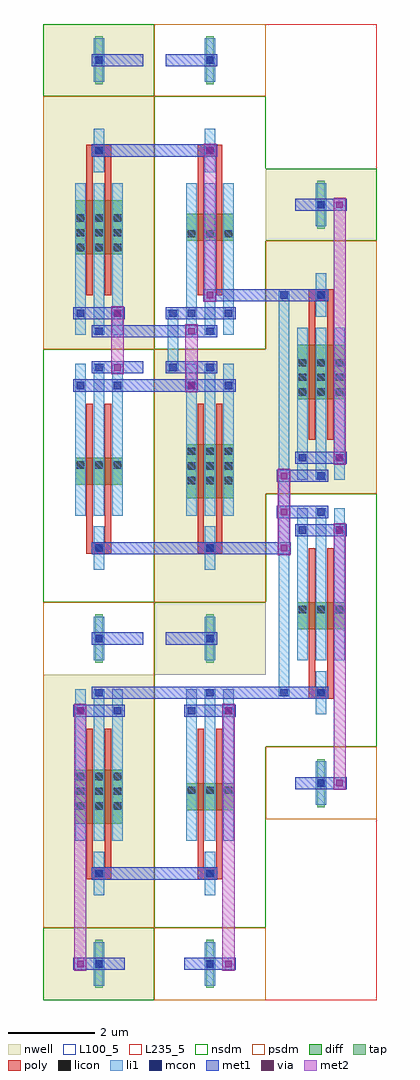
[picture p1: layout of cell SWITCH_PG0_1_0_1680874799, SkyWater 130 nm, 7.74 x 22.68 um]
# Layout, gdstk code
from math import pi, radians
import gdstk
lib = gdstk.Library(unit=1e-6, precision=1e-09)
def R(c, l, rs):  # rectangles x0, y0, x1, y1
    for r in rs: c.add(gdstk.rectangle(r[:2], r[2:], *l))
def A(c, l, x, y, w, h, nx, ny, dx, dy):  # array of equal rectangles
    R(c, l, [(x+i*dx, y+j*dy, x+i*dx+w, y+j*dy+h) for i in range(nx) for j in range(ny)])
def P(c, l, *ps):  # polygons
    for p in ps: c.add(gdstk.Polygon(p, *l))
nwell = (64, 20)
diff = (65, 20)
tap = (65, 44)
poly = (66, 20)
licon = (66, 44)
li1 = (67, 20)
mcon = (67, 44)
met1 = (68, 20)
via = (68, 44)
met2 = (69, 20)
nsdm = (93, 44)
psdm = (94, 20)
L100_5 = (100, 5)
L235_5 = (235, 5)

nmos_s_18927041_x1_y1_16 = lib.new_cell('NMOS_S_18927041_X1_Y1_1680874795_1680874799')
R(nmos_s_18927041_x1_y1_16, diff, [(0.735,2.52,1.845,3.15)])
R(nmos_s_18927041_x1_y1_16, tap, [(1.205,6.16,1.375,7.28)])
R(nmos_s_18927041_x1_y1_16, poly, [(1,1.26,1.15,4.62), (1.43,1.26,1.58,4.62), (1,4.485,1.58,4.755)])
A(nmos_s_18927041_x1_y1_16, licon, 0.775, 2.6, 0.17, 0.17, 3, 1, 0.43, 0)
R(nmos_s_18927041_x1_y1_16, licon, [(1.205,4.535,1.375,4.705), (1.205,6.635,1.375,6.805)])
A(nmos_s_18927041_x1_y1_16, li1, 0.735, 0.335, 0.25, 3.53, 3, 1, 0.43, 0)
R(nmos_s_18927041_x1_y1_16, li1, [(1.165,4.115,1.415,5.125), (1.165,6.215,1.415,7.225)])
R(nmos_s_18927041_x1_y1_16, mcon, [(1.205,0.335,1.375,0.505), (0.775,0.755,0.945,0.925), (1.635,0.755,1.805,0.925), (1.205,4.535,1.375,4.705), (1.205,6.635,1.375,6.805)])
R(nmos_s_18927041_x1_y1_16, met1, [(0.26,0.28,1.46,0.56), (0.69,0.7,1.89,0.98), (0.26,4.48,1.46,4.76), (0.69,6.58,1.89,6.86)])
R(nmos_s_18927041_x1_y1_16, via, [(1.645,0.765,1.795,0.915), (1.645,6.645,1.795,6.795)])
R(nmos_s_18927041_x1_y1_16, met2, [(1.58,0.68,1.86,6.88)])
R(nmos_s_18927041_x1_y1_16, nsdm, [(0,0,2.58,5.88)])
R(nmos_s_18927041_x1_y1_16, psdm, [(0,5.88,2.58,7.56)])
R(nmos_s_18927041_x1_y1_16, L100_5, [(0,0,2.58,7.56)])

pmos_s_92403763_x1_y1_16 = lib.new_cell('PMOS_S_92403763_X1_Y1_1680874798_1680874799')
R(pmos_s_92403763_x1_y1_16, nwell, [(0,0,2.58,7.56)])
R(pmos_s_92403763_x1_y1_16, diff, [(0.735,2.205,1.845,3.465)])
R(pmos_s_92403763_x1_y1_16, tap, [(1.205,6.16,1.375,7.28)])
R(pmos_s_92403763_x1_y1_16, poly, [(1,1.26,1.15,4.62), (1.43,1.26,1.58,4.62), (1,4.485,1.58,4.755)])
A(pmos_s_92403763_x1_y1_16, licon, 0.775, 2.285, 0.17, 0.17, 3, 3, 0.43, 0.34)
R(pmos_s_92403763_x1_y1_16, licon, [(1.205,4.535,1.375,4.705), (1.205,6.635,1.375,6.805)])
A(pmos_s_92403763_x1_y1_16, li1, 0.735, 0.335, 0.25, 3.53, 3, 1, 0.43, 0)
R(pmos_s_92403763_x1_y1_16, li1, [(1.165,4.115,1.415,5.125), (1.165,6.215,1.415,7.225)])
R(pmos_s_92403763_x1_y1_16, mcon, [(1.205,0.335,1.375,0.505), (0.775,0.755,0.945,0.925), (1.635,0.755,1.805,0.925), (1.205,4.535,1.375,4.705), (1.205,6.635,1.375,6.805)])
R(pmos_s_92403763_x1_y1_16, met1, [(0.26,0.28,1.46,0.56), (0.69,0.7,1.89,0.98), (0.26,4.48,1.46,4.76), (0.69,6.58,1.89,6.86)])
R(pmos_s_92403763_x1_y1_16, via, [(1.645,0.765,1.795,0.915), (1.645,6.645,1.795,6.795)])
R(pmos_s_92403763_x1_y1_16, met2, [(1.58,0.68,1.86,6.88)])
R(pmos_s_92403763_x1_y1_16, nsdm, [(0,5.88,2.58,7.56)])
R(pmos_s_92403763_x1_y1_16, psdm, [(0,0,2.58,5.88)])
R(pmos_s_92403763_x1_y1_16, L100_5, [(0,0,2.58,7.56)])

nmos_4t_61184386_x1_y1_1 = lib.new_cell('NMOS_4T_61184386_X1_Y1_1680874794_1680874799')
R(nmos_4t_61184386_x1_y1_1, diff, [(0.735,2.52,1.845,3.15)])
R(nmos_4t_61184386_x1_y1_1, tap, [(1.205,6.16,1.375,7.28)])
R(nmos_4t_61184386_x1_y1_1, poly, [(1,1.26,1.15,4.62), (1.43,1.26,1.58,4.62), (1,4.485,1.58,4.755)])
A(nmos_4t_61184386_x1_y1_1, licon, 0.775, 2.6, 0.17, 0.17, 3, 1, 0.43, 0)
R(nmos_4t_61184386_x1_y1_1, licon, [(1.205,4.535,1.375,4.705), (1.205,6.635,1.375,6.805)])
A(nmos_4t_61184386_x1_y1_1, li1, 0.735, 0.335, 0.25, 3.53, 3, 1, 0.43, 0)
R(nmos_4t_61184386_x1_y1_1, li1, [(1.165,4.115,1.415,5.125), (1.165,6.215,1.415,7.225)])
R(nmos_4t_61184386_x1_y1_1, mcon, [(1.205,0.335,1.375,0.505), (0.775,0.755,0.945,0.925), (1.635,0.755,1.805,0.925), (1.205,4.535,1.375,4.705), (1.205,6.635,1.375,6.805)])
R(nmos_4t_61184386_x1_y1_1, met1, [(0.26,0.28,1.46,0.56), (0.69,0.7,1.89,0.98), (0.26,4.48,1.46,4.76), (0.26,6.58,1.46,6.86)])
R(nmos_4t_61184386_x1_y1_1, nsdm, [(0,0,2.58,5.88)])
R(nmos_4t_61184386_x1_y1_1, psdm, [(0,5.88,2.58,7.56)])
R(nmos_4t_61184386_x1_y1_1, L100_5, [(0,0,2.58,7.56)])

pmos_4t_75629612_x1_y1_1 = lib.new_cell('PMOS_4T_75629612_X1_Y1_1680874796_1680874799')
R(pmos_4t_75629612_x1_y1_1, nwell, [(0,0,2.58,7.56)])
R(pmos_4t_75629612_x1_y1_1, diff, [(0.735,2.205,1.845,3.465)])
R(pmos_4t_75629612_x1_y1_1, tap, [(1.205,6.16,1.375,7.28)])
R(pmos_4t_75629612_x1_y1_1, poly, [(1,1.26,1.15,4.62), (1.43,1.26,1.58,4.62), (1,4.485,1.58,4.755)])
A(pmos_4t_75629612_x1_y1_1, licon, 0.775, 2.285, 0.17, 0.17, 3, 3, 0.43, 0.34)
R(pmos_4t_75629612_x1_y1_1, licon, [(1.205,4.535,1.375,4.705), (1.205,6.635,1.375,6.805)])
A(pmos_4t_75629612_x1_y1_1, li1, 0.735, 0.335, 0.25, 3.53, 3, 1, 0.43, 0)
R(pmos_4t_75629612_x1_y1_1, li1, [(1.165,4.115,1.415,5.125), (1.165,6.215,1.415,7.225)])
R(pmos_4t_75629612_x1_y1_1, mcon, [(1.205,0.335,1.375,0.505), (0.775,0.755,0.945,0.925), (1.635,0.755,1.805,0.925), (1.205,4.535,1.375,4.705), (1.205,6.635,1.375,6.805)])
R(pmos_4t_75629612_x1_y1_1, met1, [(0.26,0.28,1.46,0.56), (0.69,0.7,1.89,0.98), (0.26,4.48,1.46,4.76), (0.26,6.58,1.46,6.86)])
R(pmos_4t_75629612_x1_y1_1, nsdm, [(0,5.88,2.58,7.56)])
R(pmos_4t_75629612_x1_y1_1, psdm, [(0,0,2.58,5.88)])
R(pmos_4t_75629612_x1_y1_1, L100_5, [(0,0,2.58,7.56)])

pmos_4t_96318590_x1_y1_1 = lib.new_cell('PMOS_4T_96318590_X1_Y1_1680874797_1680874799')
R(pmos_4t_96318590_x1_y1_1, nwell, [(0,0,2.58,7.56)])
R(pmos_4t_96318590_x1_y1_1, diff, [(0.735,2.205,1.845,3.465)])
R(pmos_4t_96318590_x1_y1_1, tap, [(1.205,6.16,1.375,7.28)])
R(pmos_4t_96318590_x1_y1_1, poly, [(1,1.26,1.15,4.62), (1.43,1.26,1.58,4.62), (1,4.485,1.58,4.755)])
A(pmos_4t_96318590_x1_y1_1, licon, 0.775, 2.285, 0.17, 0.17, 3, 3, 0.43, 0.34)
R(pmos_4t_96318590_x1_y1_1, licon, [(1.205,4.535,1.375,4.705), (1.205,6.635,1.375,6.805)])
A(pmos_4t_96318590_x1_y1_1, li1, 0.735, 0.335, 0.25, 3.53, 3, 1, 0.43, 0)
R(pmos_4t_96318590_x1_y1_1, li1, [(1.165,4.115,1.415,5.125), (1.165,6.215,1.415,7.225)])
R(pmos_4t_96318590_x1_y1_1, mcon, [(1.205,0.335,1.375,0.505), (0.775,0.755,0.945,0.925), (1.635,0.755,1.805,0.925), (1.205,4.535,1.375,4.705), (1.205,6.635,1.375,6.805)])
R(pmos_4t_96318590_x1_y1_1, met1, [(0.26,0.28,1.46,0.56), (0.69,0.7,1.89,0.98), (0.26,4.48,1.46,4.76), (0.26,6.58,1.46,6.86)])
R(pmos_4t_96318590_x1_y1_1, nsdm, [(0,5.88,2.58,7.56)])
R(pmos_4t_96318590_x1_y1_1, psdm, [(0,0,2.58,5.88)])
R(pmos_4t_96318590_x1_y1_1, L100_5, [(0,0,2.58,7.56)])

switch_pg0_1_0_168087479 = lib.new_cell('SWITCH_PG0_1_0_1680874799')
R(switch_pg0_1_0_168087479, li1, [(5.465,7.055,5.715,7.225), (5.465,7.055,5.715,7.225), (5.465,7.055,5.715,7.225), (5.465,7.055,5.715,7.225), (5.465,7.055,5.715,7.225), (5.465,7.055,5.715,7.225), (5.465,7.14,5.715,16.38), (2.885,14.615,3.135,14.785), (2.885,14.615,3.135,14.785), (2.885,14.7,3.135,15.96), (2.885,15.875,3.135,16.045), (2.885,15.875,3.135,16.045), (5.465,16.295,5.715,16.465), (5.465,16.295,5.715,16.465), (5.465,16.295,5.715,16.465), (5.465,16.295,5.715,16.465), (5.465,16.295,5.715,16.465), (5.465,16.295,5.715,16.465)])
R(switch_pg0_1_0_168087479, mcon, [(5.505,7.055,5.675,7.225), (5.505,7.055,5.675,7.225), (5.505,7.055,5.675,7.225), (5.505,7.055,5.675,7.225), (5.505,7.055,5.675,7.225), (5.505,7.055,5.675,7.225), (2.925,14.615,3.095,14.785), (2.925,14.615,3.095,14.785), (2.925,15.875,3.095,16.045), (2.925,15.875,3.095,16.045), (5.505,16.295,5.675,16.465), (5.505,16.295,5.675,16.465), (5.505,16.295,5.675,16.465), (5.505,16.295,5.675,16.465), (5.505,16.295,5.675,16.465), (5.505,16.295,5.675,16.465)])
R(switch_pg0_1_0_168087479, met1, [(2.15,2.8,3.01,3.08), (2.15,7,3.01,7.28), (3.87,7,5.59,7.28), (5.42,7,5.76,7.28), (5.42,7,5.76,7.28), (5.42,7,5.76,7.28), (5.42,7,5.76,7.28), (5.42,7,5.76,7.28), (5.42,7,5.76,7.28), (2.15,10.36,3.01,10.64), (3.87,10.36,5.59,10.64), (5.43,10.36,5.75,10.64), (5.43,10.36,5.75,10.64), (5.43,10.36,5.75,10.64), (5.43,10.36,5.75,10.64), (5.43,11.2,5.75,11.48), (5.43,11.2,5.75,11.48), (5.43,11.2,5.75,11.48), (5.43,11.2,5.75,11.48), (5.43,11.2,5.75,11.48), (5.43,11.2,5.75,11.48), (5.43,12.04,5.75,12.32), (5.43,12.04,5.75,12.32), (5.43,12.04,5.75,12.32), (5.43,12.04,5.75,12.32), (5.43,12.04,5.75,12.32), (5.43,12.04,5.75,12.32), (1.72,14.14,3.44,14.42), (3.28,14.14,3.6,14.42), (3.28,14.14,3.6,14.42), (3.28,14.14,3.6,14.42), (3.28,14.14,3.6,14.42), (3.28,14.14,3.6,14.42), (3.28,14.14,3.6,14.42), (1.56,14.56,1.88,14.84), (1.56,14.56,1.88,14.84), (2.84,14.56,3.18,14.84), (2.84,14.56,3.18,14.84), (2.15,15.4,3.01,15.68), (3.28,15.4,3.6,15.68), (3.28,15.4,3.6,15.68), (3.28,15.4,3.6,15.68), (3.28,15.4,3.6,15.68), (3.28,15.4,3.6,15.68), (3.28,15.4,3.6,15.68), (1.56,15.82,1.88,16.1), (1.56,15.82,1.88,16.1), (2.84,15.82,3.18,16.1), (2.84,15.82,3.18,16.1), (3.01,15.82,3.44,16.1), (3.71,16.24,4.03,16.52), (3.71,16.24,4.03,16.52), (3.71,16.24,4.03,16.52), (3.71,16.24,4.03,16.52), (3.71,16.24,4.03,16.52), (3.71,16.24,4.03,16.52), (3.71,16.24,4.03,16.52), (3.71,16.24,4.03,16.52), (3.87,16.24,5.59,16.52), (5.42,16.24,5.76,16.52), (5.42,16.24,5.76,16.52), (5.42,16.24,5.76,16.52), (5.42,16.24,5.76,16.52), (5.42,16.24,5.76,16.52), (5.42,16.24,5.76,16.52), (2.15,19.6,3.01,19.88), (3.71,19.6,4.03,19.88), (3.71,19.6,4.03,19.88), (3.71,19.6,4.03,19.88), (3.71,19.6,4.03,19.88), (3.71,19.6,4.03,19.88), (3.71,19.6,4.03,19.88), (3.71,19.6,4.03,19.88), (3.71,19.6,4.03,19.88)])
P(switch_pg0_1_0_168087479, met1, [(0,0),(0,0),(0,0),(0,0)],
  [(0,0),(0,0),(0,0),(0,0)],
  [(0,0),(0,0),(0,0),(0,0)],
  [(0,0),(0,0),(0,0),(0,0)],
  [(0,0),(0,0),(0,0),(0,0)],
  [(0,0),(0,0),(0,0),(0,0)],
  [(0,0),(0,0),(0,0),(0,0)],
  [(0,0),(0,0),(0,0),(0,0)],
  [(0,0),(0,0),(0,0),(0,0)],
  [(0,0),(0,0),(0,0),(0,0)],
  [(0,0),(0,0),(0,0),(0,0)],
  [(0,0),(0,0),(0,0),(0,0)],
  [(0,0),(0,0),(0,0),(0,0)],
  [(0,0),(0,0),(0,0),(0,0)],
  [(0,0),(0,0),(0,0),(0,0)],
  [(0,0),(0,0),(0,0),(0,0)],
  [(0,0),(0,0),(0,0),(0,0)],
  [(0,0),(0,0),(0,0),(0,0)],
  [(0,0),(0,0),(0,0),(0,0)],
  [(0,0),(0,0),(0,0),(0,0)],
  [(0,0),(0,0),(0,0),(0,0)],
  [(0,0),(0,0),(0,0),(0,0)],
  [(0,0),(0,0),(0,0),(0,0)],
  [(0,0),(0,0),(0,0),(0,0)])
R(switch_pg0_1_0_168087479, via, [(5.515,10.425,5.665,10.575), (5.515,10.425,5.665,10.575), (5.515,10.425,5.665,10.575), (5.515,10.425,5.665,10.575), (5.515,11.265,5.665,11.415), (5.515,11.265,5.665,11.415), (5.515,11.265,5.665,11.415), (5.515,11.265,5.665,11.415), (5.515,11.265,5.665,11.415), (5.515,11.265,5.665,11.415), (5.515,12.105,5.665,12.255), (5.515,12.105,5.665,12.255), (5.515,12.105,5.665,12.255), (5.515,12.105,5.665,12.255), (5.515,12.105,5.665,12.255), (5.515,12.105,5.665,12.255), (3.365,14.205,3.515,14.355), (3.365,14.205,3.515,14.355), (3.365,14.205,3.515,14.355), (3.365,14.205,3.515,14.355), (3.365,14.205,3.515,14.355), (3.365,14.205,3.515,14.355), (1.645,14.625,1.795,14.775), (1.645,14.625,1.795,14.775), (3.365,15.465,3.515,15.615), (3.365,15.465,3.515,15.615), (3.365,15.465,3.515,15.615), (3.365,15.465,3.515,15.615), (3.365,15.465,3.515,15.615), (3.365,15.465,3.515,15.615), (1.645,15.885,1.795,16.035), (1.645,15.885,1.795,16.035), (3.795,16.305,3.945,16.455), (3.795,16.305,3.945,16.455), (3.795,16.305,3.945,16.455), (3.795,16.305,3.945,16.455), (3.795,16.305,3.945,16.455), (3.795,16.305,3.945,16.455), (3.795,16.305,3.945,16.455), (3.795,16.305,3.945,16.455), (3.795,19.665,3.945,19.815), (3.795,19.665,3.945,19.815), (3.795,19.665,3.945,19.815), (3.795,19.665,3.945,19.815), (3.795,19.665,3.945,19.815), (3.795,19.665,3.945,19.815), (3.795,19.665,3.945,19.815), (3.795,19.665,3.945,19.815)])
R(switch_pg0_1_0_168087479, met2, [(5.45,10.34,5.73,10.66), (5.45,10.34,5.73,10.66), (5.45,10.34,5.73,10.66), (5.45,10.34,5.73,10.66), (5.45,10.5,5.73,11.34), (5.45,11.18,5.73,11.5), (5.45,11.18,5.73,11.5), (5.45,11.18,5.73,11.5), (5.45,11.18,5.73,11.5), (5.45,11.18,5.73,11.5), (5.45,11.18,5.73,11.5), (5.45,11.34,5.73,12.18), (5.45,12.02,5.73,12.34), (5.45,12.02,5.73,12.34), (5.45,12.02,5.73,12.34), (5.45,12.02,5.73,12.34), (5.45,12.02,5.73,12.34), (5.45,12.02,5.73,12.34), (3.3,14.12,3.58,14.44), (3.3,14.12,3.58,14.44), (3.3,14.12,3.58,14.44), (3.3,14.12,3.58,14.44), (3.3,14.12,3.58,14.44), (3.3,14.12,3.58,14.44), (3.3,14.28,3.58,15.54), (1.58,14.54,1.86,14.86), (1.58,14.54,1.86,14.86), (1.58,14.7,1.86,15.96), (3.3,15.38,3.58,15.7), (3.3,15.38,3.58,15.7), (3.3,15.38,3.58,15.7), (3.3,15.38,3.58,15.7), (3.3,15.38,3.58,15.7), (3.3,15.38,3.58,15.7), (1.58,15.8,1.86,16.12), (1.58,15.8,1.86,16.12), (3.73,16.22,4.01,16.54), (3.73,16.22,4.01,16.54), (3.73,16.22,4.01,16.54), (3.73,16.22,4.01,16.54), (3.73,16.22,4.01,16.54), (3.73,16.22,4.01,16.54), (3.73,16.22,4.01,16.54), (3.73,16.22,4.01,16.54), (3.73,16.38,4.01,19.74), (3.73,19.58,4.01,19.9), (3.73,19.58,4.01,19.9), (3.73,19.58,4.01,19.9), (3.73,19.58,4.01,19.9), (3.73,19.58,4.01,19.9), (3.73,19.58,4.01,19.9), (3.73,19.58,4.01,19.9), (3.73,19.58,4.01,19.9)])
P(switch_pg0_1_0_168087479, met2, [(0,0),(0,0),(0,0),(0,0)],
  [(0,0),(0,0),(0,0),(0,0)],
  [(0,0),(0,0),(0,0),(0,0)],
  [(0,0),(0,0),(0,0),(0,0)])
R(switch_pg0_1_0_168087479, L235_5, [(0,0,7.74,22.68)])
switch_pg0_1_0_168087479.add(gdstk.Reference(nmos_s_18927041_x1_y1_16, (2.58,7.56), x_reflection=True))
switch_pg0_1_0_168087479.add(gdstk.Reference(nmos_s_18927041_x1_y1_16, (5.16,11.76), x_reflection=True))
switch_pg0_1_0_168087479.add(gdstk.Reference(pmos_s_92403763_x1_y1_16, (2.58,7.56), rotation=pi))
switch_pg0_1_0_168087479.add(gdstk.Reference(pmos_s_92403763_x1_y1_16, (5.16,11.76)))
switch_pg0_1_0_168087479.add(gdstk.Reference(nmos_4t_61184386_x1_y1_1, (2.58,15.12), rotation=pi))
switch_pg0_1_0_168087479.add(gdstk.Reference(nmos_4t_61184386_x1_y1_1, (2.58,15.12)))
switch_pg0_1_0_168087479.add(gdstk.Reference(pmos_4t_75629612_x1_y1_1, (2.58,15.12), x_reflection=True))
switch_pg0_1_0_168087479.add(gdstk.Reference(pmos_4t_96318590_x1_y1_1, (2.58,15.12), rotation=pi, x_reflection=True))

lib.write_gds('SWITCH_PG0_1_0_1680874799.gds')
